VERSION 5.7 ;
  NOWIREEXTENSIONATPIN ON ;
  DIVIDERCHAR "/" ;
  BUSBITCHARS "[]" ;
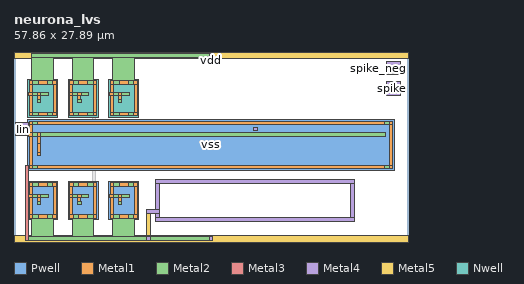
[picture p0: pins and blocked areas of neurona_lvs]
MACRO neurona_lvs
  CLASS BLOCK ;
  FOREIGN neurona_lvs ;
  ORIGIN 0.000 0.000 ;
  SIZE 57.860 BY 27.890 ;
  PIN vss
    USE GROUND ;
    ANTENNADIFFAREA 62.992199 ;
    PORT
      LAYER Pwell ;
        RECT 2.000 10.545 55.860 17.935 ;
        RECT 2.000 3.300 6.440 8.900 ;
        RECT 7.940 3.300 12.380 8.900 ;
        RECT 13.880 3.300 18.320 8.900 ;
      LAYER Metal1 ;
        RECT 2.230 17.225 2.730 17.725 ;
        RECT 3.480 17.225 54.380 17.725 ;
        RECT 55.130 17.225 55.630 17.725 ;
        RECT 2.230 16.035 2.690 17.225 ;
        RECT 2.190 15.535 2.690 16.035 ;
        RECT 3.400 15.535 3.900 16.035 ;
        RECT 2.230 11.255 2.690 15.535 ;
        RECT 3.420 14.485 3.880 15.535 ;
        RECT 3.400 13.185 3.900 14.485 ;
        RECT 3.420 12.685 3.880 13.185 ;
        RECT 55.170 11.255 55.630 17.225 ;
        RECT 2.230 10.755 2.730 11.255 ;
        RECT 3.480 10.755 54.380 11.255 ;
        RECT 55.130 10.755 55.630 11.255 ;
        RECT 2.230 8.190 2.730 8.690 ;
        RECT 3.570 8.190 4.870 8.690 ;
        RECT 5.710 8.190 6.210 8.690 ;
        RECT 2.230 6.995 2.690 8.190 ;
        RECT 2.190 6.495 2.690 6.995 ;
        RECT 3.400 6.495 3.900 6.995 ;
        RECT 2.230 4.010 2.690 6.495 ;
        RECT 3.420 5.945 3.880 6.495 ;
        RECT 3.400 5.445 3.900 5.945 ;
        RECT 5.750 4.010 6.210 8.190 ;
        RECT 8.170 8.190 8.670 8.690 ;
        RECT 9.510 8.190 10.810 8.690 ;
        RECT 11.650 8.190 12.150 8.690 ;
        RECT 8.170 6.995 8.630 8.190 ;
        RECT 8.130 6.495 8.630 6.995 ;
        RECT 9.340 6.495 9.840 6.995 ;
        RECT 2.230 3.510 2.730 4.010 ;
        RECT 3.570 3.510 4.870 4.010 ;
        RECT 5.710 3.510 6.210 4.010 ;
        RECT 8.170 4.010 8.630 6.495 ;
        RECT 9.360 5.945 9.820 6.495 ;
        RECT 9.340 5.445 9.840 5.945 ;
        RECT 11.690 4.010 12.150 8.190 ;
        RECT 14.110 8.190 14.610 8.690 ;
        RECT 15.450 8.190 16.750 8.690 ;
        RECT 17.590 8.190 18.090 8.690 ;
        RECT 14.110 6.995 14.570 8.190 ;
        RECT 14.070 6.495 14.570 6.995 ;
        RECT 15.280 6.495 15.780 6.995 ;
        RECT 8.170 3.510 8.670 4.010 ;
        RECT 9.510 3.510 10.810 4.010 ;
        RECT 11.650 3.510 12.150 4.010 ;
        RECT 14.110 4.010 14.570 6.495 ;
        RECT 15.300 5.945 15.760 6.495 ;
        RECT 15.280 5.445 15.780 5.945 ;
        RECT 17.630 4.010 18.090 8.190 ;
        RECT 14.110 3.510 14.610 4.010 ;
        RECT 15.450 3.510 16.750 4.010 ;
        RECT 17.590 3.510 18.090 4.010 ;
      LAYER Metal2 ;
        RECT 2.230 17.225 55.630 17.725 ;
        RECT 2.190 15.535 54.460 16.035 ;
        RECT 3.400 12.685 3.900 14.985 ;
        RECT 1.640 10.755 55.630 11.255 ;
        RECT 2.230 8.190 6.210 8.690 ;
        RECT 8.170 8.190 12.150 8.690 ;
        RECT 14.110 8.190 18.090 8.690 ;
        RECT 2.190 6.495 5.040 6.995 ;
        RECT 8.130 6.495 10.980 6.995 ;
        RECT 14.070 6.495 16.920 6.995 ;
        RECT 3.400 5.445 3.900 5.945 ;
        RECT 9.340 5.445 9.840 5.945 ;
        RECT 15.280 5.445 15.780 5.945 ;
        RECT 2.230 3.510 6.210 4.010 ;
        RECT 8.170 3.510 12.150 4.010 ;
        RECT 14.110 3.510 18.090 4.010 ;
        RECT 2.640 0.750 5.800 3.510 ;
        RECT 8.580 0.750 11.740 3.510 ;
        RECT 14.520 0.750 17.680 3.510 ;
        RECT 1.640 0.250 29.180 0.750 ;
      LAYER Metal3 ;
        RECT 1.640 0.250 2.140 11.255 ;
        RECT 19.470 0.250 19.970 0.750 ;
        RECT 28.680 0.250 29.180 0.750 ;
      LAYER Metal4 ;
        RECT 20.820 8.600 50.020 9.200 ;
        RECT 20.820 4.750 21.420 8.600 ;
        RECT 19.470 4.250 21.420 4.750 ;
        RECT 20.820 3.600 21.420 4.250 ;
        RECT 49.420 3.600 50.020 8.600 ;
        RECT 20.820 3.000 50.020 3.600 ;
        RECT 19.470 0.250 19.970 0.750 ;
        RECT 28.680 0.250 29.180 0.750 ;
      LAYER Metal5 ;
        RECT 19.470 1.000 19.970 4.750 ;
        RECT 0.000 0.000 57.860 1.000 ;
    END
  END vss
  PIN vdd
    USE POWER ;
    ANTENNADIFFAREA 18.837000 ;
    PORT
      LAYER Nwell ;
        RECT 2.000 18.290 6.440 23.890 ;
        RECT 7.940 18.290 12.380 23.890 ;
        RECT 13.880 18.290 18.320 23.890 ;
      LAYER Metal1 ;
        RECT 2.230 23.180 2.730 23.680 ;
        RECT 3.570 23.180 4.870 23.680 ;
        RECT 5.710 23.180 6.210 23.680 ;
        RECT 2.230 21.985 2.690 23.180 ;
        RECT 2.190 21.485 2.690 21.985 ;
        RECT 3.400 21.485 3.900 21.985 ;
        RECT 2.230 19.000 2.690 21.485 ;
        RECT 3.420 20.935 3.880 21.485 ;
        RECT 3.400 20.435 3.900 20.935 ;
        RECT 5.750 19.000 6.210 23.180 ;
        RECT 8.170 23.180 8.670 23.680 ;
        RECT 9.510 23.180 10.810 23.680 ;
        RECT 11.650 23.180 12.150 23.680 ;
        RECT 8.170 21.985 8.630 23.180 ;
        RECT 8.130 21.485 8.630 21.985 ;
        RECT 9.340 21.485 9.840 21.985 ;
        RECT 2.230 18.500 2.730 19.000 ;
        RECT 3.570 18.500 4.870 19.000 ;
        RECT 5.710 18.500 6.210 19.000 ;
        RECT 8.170 19.000 8.630 21.485 ;
        RECT 9.360 20.935 9.820 21.485 ;
        RECT 9.340 20.435 9.840 20.935 ;
        RECT 11.690 19.000 12.150 23.180 ;
        RECT 14.110 23.180 14.610 23.680 ;
        RECT 15.450 23.180 16.750 23.680 ;
        RECT 17.590 23.180 18.090 23.680 ;
        RECT 14.110 21.985 14.570 23.180 ;
        RECT 14.070 21.485 14.570 21.985 ;
        RECT 15.280 21.485 15.780 21.985 ;
        RECT 8.170 18.500 8.670 19.000 ;
        RECT 9.510 18.500 10.810 19.000 ;
        RECT 11.650 18.500 12.150 19.000 ;
        RECT 14.110 19.000 14.570 21.485 ;
        RECT 15.300 20.935 15.760 21.485 ;
        RECT 15.280 20.435 15.780 20.935 ;
        RECT 17.630 19.000 18.090 23.180 ;
        RECT 14.110 18.500 14.610 19.000 ;
        RECT 15.450 18.500 16.750 19.000 ;
        RECT 17.590 18.500 18.090 19.000 ;
      LAYER Metal2 ;
        RECT 2.640 27.140 29.180 27.640 ;
        RECT 2.640 23.680 5.800 27.140 ;
        RECT 8.580 23.680 11.740 27.140 ;
        RECT 14.520 23.680 17.680 27.140 ;
        RECT 2.230 23.180 6.210 23.680 ;
        RECT 8.170 23.180 12.150 23.680 ;
        RECT 14.110 23.180 18.090 23.680 ;
        RECT 2.190 21.485 5.040 21.985 ;
        RECT 8.130 21.485 10.980 21.985 ;
        RECT 14.070 21.485 16.920 21.985 ;
        RECT 3.400 20.435 3.900 20.935 ;
        RECT 9.340 20.435 9.840 20.935 ;
        RECT 15.280 20.435 15.780 20.935 ;
        RECT 2.230 18.500 6.210 19.000 ;
        RECT 8.170 18.500 12.150 19.000 ;
        RECT 14.110 18.500 18.090 19.000 ;
      LAYER Metal3 ;
        RECT 28.680 27.140 29.180 27.640 ;
      LAYER Metal4 ;
        RECT 28.680 27.140 29.180 27.640 ;
      LAYER Metal5 ;
        RECT 0.000 26.890 57.860 27.890 ;
    END
  END vdd
  PIN Iin
    ANTENNAGATEAREA 0.280000 ;
    ANTENNADIFFAREA 1.380000 ;
    PORT

      LAYER Metal4 ;
        RECT 0.150 15.585 2.150 17.585 ;
        RECT 35.170 16.335 35.670 16.835 ;

    END
  END Iin
  PIN spike_neg
    ANTENNAGATEAREA 0.560000 ;
    ANTENNADIFFAREA 0.750000 ;
    PORT

      LAYER Metal4 ;
        RECT 54.670 24.535 56.670 26.535 ;
    END
  END spike_neg
  PIN spike
    ANTENNADIFFAREA 0.750000 ;
    PORT

      LAYER Metal4 ;
        RECT 54.670 21.535 56.670 23.535 ;
    END
  END spike
  OBS
      LAYER Metal1 ;
        RECT 10.480 22.285 10.980 22.785 ;
        RECT 10.500 20.935 10.960 22.285 ;
        RECT 10.480 20.435 10.980 20.935 ;
        RECT 4.280 11.645 4.780 12.145 ;
        RECT 5.080 11.645 5.580 12.145 ;
        RECT 5.880 11.645 6.380 12.145 ;
        RECT 6.680 11.645 7.180 12.145 ;
        RECT 7.480 11.645 7.980 12.145 ;
        RECT 8.280 11.645 8.780 12.145 ;
        RECT 9.080 11.645 9.580 12.145 ;
        RECT 9.880 11.645 10.380 12.145 ;
        RECT 10.680 11.645 11.180 12.145 ;
        RECT 11.480 11.645 11.980 12.145 ;
        RECT 12.280 11.645 12.780 12.145 ;
        RECT 13.080 11.645 13.580 12.145 ;
        RECT 13.880 11.645 14.380 12.145 ;
        RECT 14.680 11.645 15.180 12.145 ;
        RECT 15.480 11.645 15.980 12.145 ;
        RECT 16.280 11.645 16.780 12.145 ;
        RECT 17.080 11.645 17.580 12.145 ;
        RECT 17.880 11.645 18.380 12.145 ;
        RECT 18.680 11.645 19.180 12.145 ;
        RECT 19.480 11.645 19.980 12.145 ;
        RECT 20.280 11.645 20.780 12.145 ;
        RECT 21.080 11.645 21.580 12.145 ;
        RECT 21.880 11.645 22.380 12.145 ;
        RECT 22.680 11.645 23.180 12.145 ;
        RECT 23.480 11.645 23.980 12.145 ;
        RECT 24.280 11.645 24.780 12.145 ;
        RECT 25.080 11.645 25.580 12.145 ;
        RECT 25.880 11.645 26.380 12.145 ;
        RECT 26.680 11.645 27.180 12.145 ;
        RECT 27.480 11.645 27.980 12.145 ;
        RECT 28.280 11.645 28.780 12.145 ;
        RECT 29.080 11.645 29.580 12.145 ;
        RECT 29.880 11.645 30.380 12.145 ;
        RECT 30.680 11.645 31.180 12.145 ;
        RECT 31.480 11.645 31.980 12.145 ;
        RECT 32.280 11.645 32.780 12.145 ;
        RECT 33.080 11.645 33.580 12.145 ;
        RECT 33.880 11.645 34.380 12.145 ;
        RECT 34.680 11.645 35.180 12.145 ;
        RECT 35.480 11.645 35.980 12.145 ;
        RECT 36.280 11.645 36.780 12.145 ;
        RECT 37.080 11.645 37.580 12.145 ;
        RECT 37.880 11.645 38.380 12.145 ;
        RECT 38.680 11.645 39.180 12.145 ;
        RECT 39.480 11.645 39.980 12.145 ;
        RECT 40.280 11.645 40.780 12.145 ;
        RECT 41.080 11.645 41.580 12.145 ;
        RECT 41.880 11.645 42.380 12.145 ;
        RECT 42.680 11.645 43.180 12.145 ;
        RECT 43.480 11.645 43.980 12.145 ;
        RECT 44.280 11.645 44.780 12.145 ;
        RECT 45.080 11.645 45.580 12.145 ;
        RECT 45.880 11.645 46.380 12.145 ;
        RECT 46.680 11.645 47.180 12.145 ;
        RECT 47.480 11.645 47.980 12.145 ;
        RECT 48.280 11.645 48.780 12.145 ;
        RECT 49.080 11.645 49.580 12.145 ;
        RECT 49.880 11.645 50.380 12.145 ;
        RECT 50.680 11.645 51.180 12.145 ;
        RECT 51.480 11.645 51.980 12.145 ;
        RECT 52.280 11.645 52.780 12.145 ;
        RECT 53.080 11.645 53.580 12.145 ;
        RECT 10.480 7.295 10.980 7.795 ;
        RECT 10.500 5.945 10.960 7.295 ;
        RECT 10.480 5.445 10.980 5.945 ;
      LAYER Metal2 ;
        RECT 9.340 22.285 11.980 22.785 ;
        RECT 10.480 20.435 10.980 20.935 ;
        RECT 3.930 11.645 53.930 12.145 ;
        RECT 9.340 7.295 11.980 7.795 ;
        RECT 10.480 5.445 10.980 5.945 ;
      LAYER Metal3 ;
        RECT 11.480 12.145 11.980 22.785 ;
        RECT 11.180 11.645 11.980 12.145 ;
        RECT 11.480 7.295 11.980 11.645 ;
  END
END neurona_lvs
END LIBRARY

